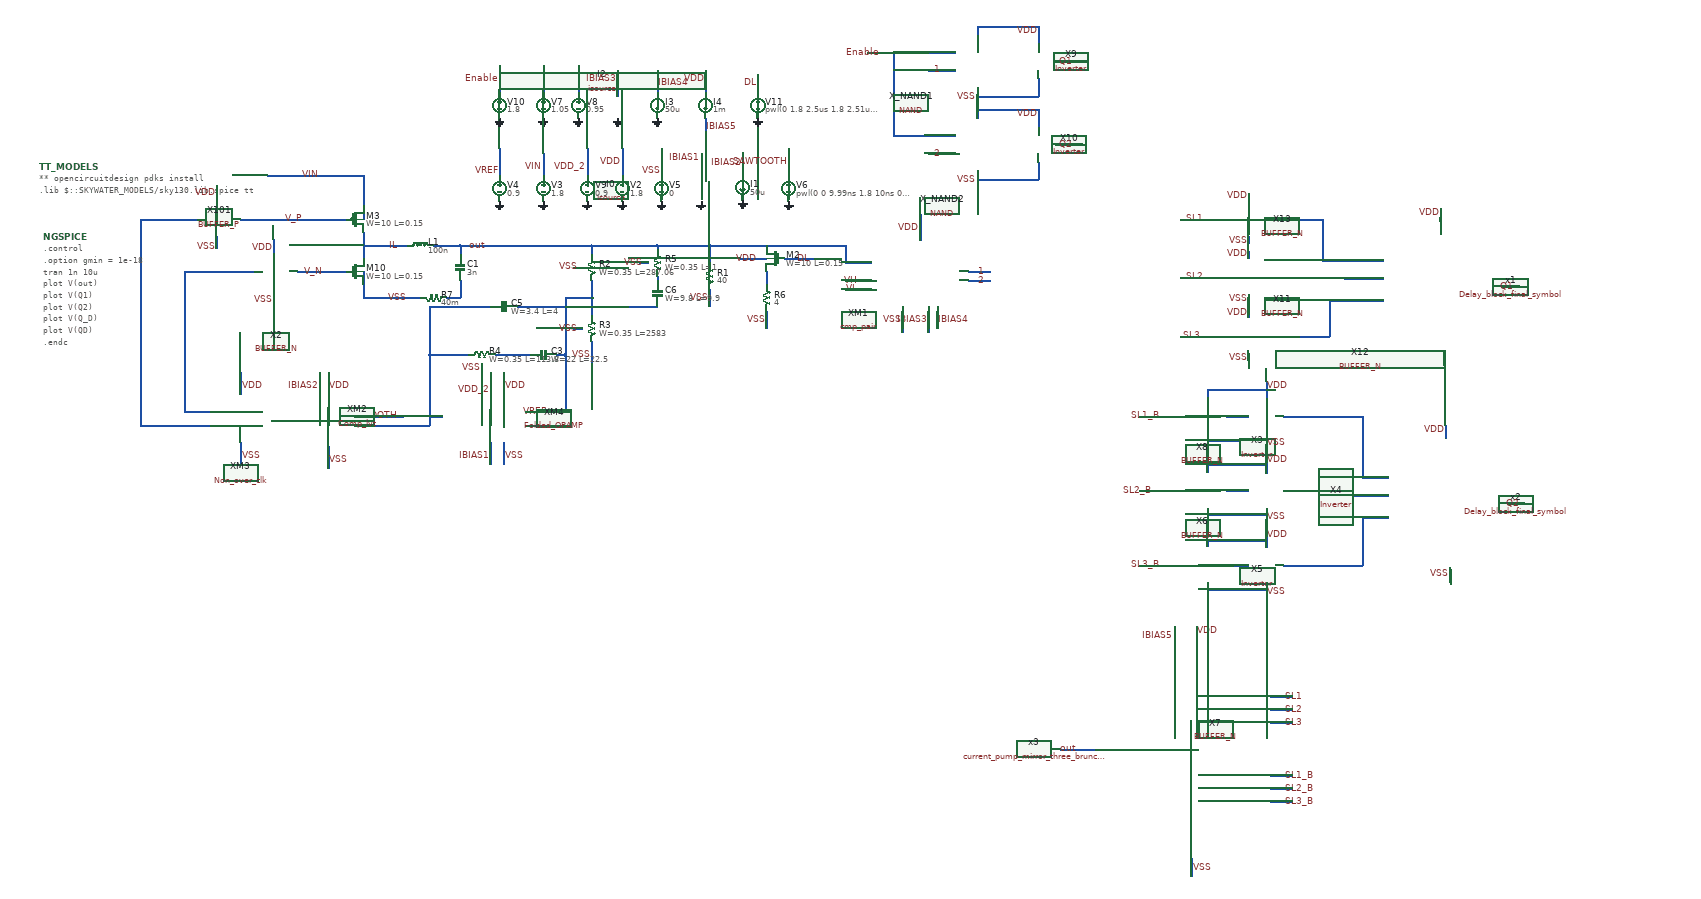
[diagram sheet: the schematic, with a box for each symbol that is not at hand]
v {xschem version=3.0.0 file_version=1.2 }
G {}
K {}
V {}
S {}
E {}
N 3270 1660 3270 1720 {
lab=IL}
N 3270 1600 3270 1630 {
lab=VIN}
N 3180 1630 3230 1630 {
lab=V_P}
N 3270 1530 3270 1600 {
lab=VIN}
N 3050 1530 3270 1530 {
lab=VIN}
N 3270 1780 3270 1810 {
lab=VSS}
N 3270 1690 3330 1690 {
lab=IL}
N 3330 1690 3370 1690 {
lab=IL}
N 3490 1690 3490 1710 {
lab=out}
N 3430 1690 3490 1690 {
lab=out}
N 3490 1770 3490 1810 {
lab=#net1}
N 3490 1690 3600 1690 {
lab=out}
N 3590 1980 3590 2030 {
lab=VDD}
N 3560 1980 3560 2030 {
lab=VDD_2}
N 3590 2140 3590 2190 {
lab=VSS}
N 3560 2140 3560 2190 {
lab=IBIAS1}
N 3640 2100 3690 2100 {
lab=#net2}
N 3640 2070 3690 2070 {
lab=VREF}
N 3680 1480 3680 1530 {
lab=VIN}
N 3780 1470 3780 1530 {
lab=VDD_2}
N 3860 1520 3860 1530 {
lab=VDD}
N 3860 1470 3860 1520 {
lab=VDD}
N 3950 1500 3950 1520 {
lab=VSS}
N 3950 1520 3950 1530 {
lab=VSS}
N 3950 1470 3950 1500 {
lab=VSS}
N 4040 1480 4040 1540 {
lab=IBIAS1}
N 3190 1980 3190 2030 {
lab=VDD}
N 3190 2150 3190 2200 {
lab=VSS}
N 3580 1500 3580 1520 {
lab=VREF}
N 3580 1520 3580 1530 {
lab=VREF}
N 3580 1470 3580 1500 {
lab=VREF}
N 3690 2100 3720 2100 {
lab=#net2}
N 3170 1980 3170 2030 {
lab=IBIAS2}
N 4240 1470 4240 1530 {
lab=SAWTOOTH}
N 2990 1630 3180 1630 {
lab=V_P}
N 3600 1690 3780 1690 {
lab=out}
N 3790 1690 3790 1710 {
lab=out}
N 3790 1770 3790 1820 {
lab=#net2}
N 3790 1910 3790 1960 {
lab=VSS}
N 3570 1940 3650 1940 {
lab=#net3}
N 3420 1940 3510 1940 {
lab=#net4}
N 3420 1940 3420 2080 {
lab=#net4}
N 3730 1940 3730 2070 {
lab=#net2}
N 3710 1940 3730 1940 {
lab=#net2}
N 3420 1830 3560 1830 {
lab=#net4}
N 3620 1830 3730 1830 {
lab=#net2}
N 3730 1870 3730 1940 {
lab=#net2}
N 3420 2080 3450 2080 {
lab=#net4}
N 3730 2070 3730 2100 {
lab=#net2}
N 3720 2100 3730 2100 {
lab=#net2}
N 3790 1690 3940 1690 {
lab=out}
N 3940 1690 3940 1700 {
lab=out}
N 3940 1760 3940 1770 {
lab=#net5}
N 3780 1690 3790 1690 {
lab=out}
N 3730 1810 3730 1870 {
lab=#net2}
N 3730 1810 3790 1810 {
lab=#net2}
N 3790 1820 3790 1850 {
lab=#net2}
N 4060 1690 4060 1730 {
lab=out}
N 3940 1690 4060 1690 {
lab=out}
N 4060 1790 4060 1830 {
lab=VSS}
N 3250 2100 3420 2100 {
lab=#net4}
N 3420 2080 3420 2100 {
lab=#net4}
N 3180 1750 3230 1750 {
lab=V_N}
N 3270 1750 3270 1780 {
lab=VSS}
N 4060 1690 4190 1690 {
lab=out}
N 4190 1840 4190 1880 {
lab=VSS}
N 4190 1750 4190 1780 {
lab=#net6}
N 4230 1720 4300 1720 {
lab=DL}
N 2990 1980 2990 2030 {
lab=VDD}
N 2990 2140 2990 2190 {
lab=VSS}
N 2760 1630 2890 1630 {
lab=#net7}
N 2760 1630 2760 2070 {
lab=#net7}
N 2935 1670 2935 1697.5 {
lab=VSS}
N 2935 1552.5 2935 1587.5 {
lab=VDD}
N 3120 1750 3180 1750 {
lab=V_N}
N 2860 1750 3020 1750 {
lab=#net8}
N 2860 1750 2860 1840 {
lab=#net8}
N 3065 1790 3065 1827.5 {
lab=VSS}
N 3065 1677.5 3065 1707.5 {
lab=VDD}
N 2860 2070 2920 2070 {
lab=#net8}
N 2860 1840 2860 2070 {
lab=#net8}
N 2760 2100 2920 2100 {
lab=#net7}
N 2760 2070 2760 2100 {
lab=#net7}
N 3420 1830 3420 1940 {
lab=#net4}
N 3790 1830 3840 1830 {
lab=#net2}
N 3840 1830 3940 1830 {
lab=#net2}
N 3590 2140 3590 2190 {
lab=VSS}
N 4130 1720 4190 1720 {
lab=VDD}
N 4135 1477.5 4135 1527.5 {
lab=IBIAS2}
N 3070 2090 3120 2090 {
lab=#net9}
N 3250 2080 3360 2080 {
lab=SAWTOOTH}
N 3540 1960 3540 1980 {
lab=VSS}
N 3900 1730 3920 1730 {
lab=VSS}
N 3750 1740 3770 1740 {
lab=VSS}
N 3750 1880 3770 1880 {
lab=VSS}
N 3270 1810 3400 1810 {
lab=VSS}
N 3460 1810 3490 1810 {
lab=#net1}
N 3060 2090 3070 2090 {
lab=#net9}
N 4650 1750 4700 1750 {
lab=1}
N 4650 1770 4700 1770 {
lab=2}
N 4580 1830 4580 1880 {
lab=IBIAS4}
N 4560 1830 4560 1890 {
lab=IBIAS3}
N 4500 1830 4500 1890 {
lab=VSS}
N 4540 1620 4540 1680 {
lab=VDD}
N 4370 1730 4430 1730 {
lab=out}
N 4370 1770 4430 1770 {
lab=VH}
N 4370 1790 4430 1790 {
lab=VL}
N 4370 1690 4370 1730 {
lab=out}
N 3680 1280 3680 1340 {
lab=VH}
N 3760 1280 3760 1340 {
lab=VL}
N 3850 1290 3850 1350 {
lab=IBIAS3}
N 3940 1290 3940 1340 {
lab=IBIAS4}
N 4480 1440 4620 1440 {
lab=Enable}
N 4480 1250 4620 1250 {
lab=Enable}
N 4420 1250 4480 1250 {
lab=Enable}
N 4560 1290 4620 1290 {
lab=1}
N 4560 1480 4620 1480 {
lab=2}
N 4850 1270 4910 1270 {
lab=Q1}
N 4850 1460 4910 1460 {
lab=Q2}
N 4910 1270 4920 1270 {
lab=Q1}
N 3580 1280 3580 1340 {
lab=Enable}
N 4170 1320 4170 1340 {
lab=DL}
N 4170 1300 4170 1320 {
lab=DL}
N 4190 1690 4370 1690 {
lab=out}
N 4670 1520 4670 1540 {
lab=VSS}
N 4670 1540 4810 1540 {
lab=VSS}
N 4810 1500 4810 1540 {
lab=VSS}
N 4670 1380 4670 1400 {
lab=VDD}
N 4670 1380 4810 1380 {
lab=VDD}
N 4810 1380 4810 1420 {
lab=VDD}
N 4670 1330 4670 1350 {
lab=VSS}
N 4670 1350 4810 1350 {
lab=VSS}
N 4810 1310 4810 1350 {
lab=VSS}
N 4670 1190 4670 1210 {
lab=VDD}
N 4670 1190 4810 1190 {
lab=VDD}
N 4810 1190 4810 1230 {
lab=VDD}
N 4480 1250 4480 1440 {
lab=Enable}
N 5727.5 1605 5727.5 1635 {
lab=VDD}
N 5867.5 1785 5907.5 1785 {
lab=Q1}
N 5737.5 1935 5737.5 1965 {
lab=VSS}
N 5547.5 1725 5597.5 1725 {
lab=#net10}
N 5547.5 1765 5597.5 1765 {
lab=#net11}
N 5547.5 1815 5597.5 1815 {
lab=#net12}
N 5740 2100 5740 2130 {
lab=VDD}
N 5880 2280 5920 2280 {
lab=Q2}
N 5750 2430 5750 2460 {
lab=VSS}
N 5240 2080 5290 2080 {
lab=#net13}
N 5240 2250 5290 2250 {
lab=#net14}
N 5240 2420 5290 2420 {
lab=#net15}
N 5330 2120 5330 2160 {
lab=VSS}
N 5330 2000 5330 2040 {
lab=VDD}
N 5330 2290 5330 2330 {
lab=VSS}
N 5330 2170 5330 2210 {
lab=VDD}
N 5330 2460 5330 2500 {
lab=VSS}
N 5330 2340 5330 2380 {
lab=VDD}
N 5550 2220 5610 2220 {
lab=#net16}
N 5550 2080 5550 2220 {
lab=#net16}
N 5370 2080 5550 2080 {
lab=#net16}
N 5370 2250 5470 2250 {
lab=#net17}
N 5470 2250 5470 2260 {
lab=#net17}
N 5470 2260 5610 2260 {
lab=#net17}
N 5550 2310 5610 2310 {
lab=#net18}
N 5550 2310 5550 2420 {
lab=#net18}
N 5370 2420 5550 2420 {
lab=#net18}
N 5170 2560 5170 2600 {
lab=VDD}
N 5340 2900 5390 2900 {
lab=SL1_B}
N 5340 2930 5390 2930 {
lab=SL2_B}
N 5340 2960 5390 2960 {
lab=SL3_B}
N 5160 3090 5160 3130 {
lab=VSS}
N 4050 1290 4050 1340 {
lab=VDD}
N 4050 1400 4050 1430 {
lab=IBIAS5}
N 5120 2560 5120 2600 {
lab=IBIAS5}
N 5340 2720 5390 2720 {
lab=SL1}
N 5340 2750 5390 2750 {
lab=SL2}
N 5340 2780 5390 2780 {
lab=SL3}
N 4860 2840 4940 2840 {
lab=out}
N 5040 2250 5140 2250 {
lab=SL2_B}
N 5040 2420 5140 2420 {
lab=SL3_B}
N 5040 2080 5140 2080 {
lab=SL1_B}
N 5195 2020 5195 2037.5 {
lab=VDD}
N 5195 2020 5330 2020 {
lab=VDD}
N 5195 2120 5195 2135 {
lab=VSS}
N 5195 2135 5330 2135 {
lab=VSS}
N 5195 2190 5195 2207.5 {
lab=VDD}
N 5195 2190 5330 2190 {
lab=VDD}
N 5195 2290 5195 2305 {
lab=VSS}
N 5195 2305 5330 2305 {
lab=VSS}
N 5195 2362.5 5195 2377.5 {
lab=VDD}
N 5195 2362.5 5330 2362.5 {
lab=VDD}
N 5195 2460 5195 2475 {
lab=VSS}
N 5195 2475 5330 2475 {
lab=VSS}
N 5135 1762.5 5235 1762.5 {
lab=SL2}
N 5135 1897.5 5235 1897.5 {
lab=SL3}
N 5135 1630 5235 1630 {
lab=SL1}
N 5290 1840 5290 1855 {
lab=VDD}
N 5290 1937.5 5290 1952.5 {
lab=VSS}
N 5290 1705 5290 1720 {
lab=VDD}
N 5290 1802.5 5290 1817.5 {
lab=VSS}
N 5290 1572.5 5290 1587.5 {
lab=VDD}
N 5290 1670 5290 1685 {
lab=VSS}
N 5457.5 1725 5547.5 1725 {
lab=#net10}
N 5457.5 1630 5457.5 1725 {
lab=#net10}
N 5335 1630 5457.5 1630 {
lab=#net10}
N 5335 1762.5 5507.5 1762.5 {
lab=#net11}
N 5507.5 1765 5547.5 1765 {
lab=#net11}
N 5507.5 1762.5 5507.5 1765 {
lab=#net11}
N 5475 1815 5547.5 1815 {
lab=#net12}
N 5475 1815 5475 1890 {
lab=#net12}
N 5475 1890 5475 1892.5 {
lab=#net12}
N 5475 1892.5 5475 1895 {
lab=#net12}
N 5475 1895 5475 1897.5 {
lab=#net12}
N 5335 1897.5 5475 1897.5 {
lab=#net12}
C {sky130_fd_pr/pfet_01v8.sym} 3250 1630 0 0 {name=M3
L=0.15
W=10
nf=1
mult=450
ad="'int((nf+1)/2) * W/nf * 0.29'" 
pd="'2*int((nf+1)/2) * (W/nf + 0.29)'"
as="'int((nf+2)/2) * W/nf * 0.29'" 
ps="'2*int((nf+2)/2) * (W/nf + 0.29)'"
nrd="'0.29 / W'" nrs="'0.29 / W'"
sa=0 sb=0 sd=0
model=pfet_01v8
spiceprefix=X
}
C {devices/ind.sym} 3400 1690 3 0 {name=L1
m=1
value=100n
footprint=1206
device=inductor}
C {devices/capa.sym} 3490 1740 0 0 {name=C1
m=1
value=3n
footprint=1206
device="ceramic capacitor"}
C {devices/code.sym} 2530 1510 0 0 {name=TT_MODELS
only_toplevel=true
format="tcleval( @value )"
value="
** opencircuitdesign pdks install
.lib $::SKYWATER_MODELS/sky130.lib.spice tt

"
spice_ignore=false}
C {devices/code_shown.sym} 2540 1670 0 0 {name=NGSPICE
only_toplevel=true
value="

.control

.option gmin = 1e-18
tran 1n 10u
plot V(out)
plot V(Q1)
plot V(Q2) 
plot V(Q_D)
plot V(QD)
.endc
" }
C {devices/lab_wire.sym} 3550 1690 0 0 {name=l4 sig_type=std_logic lab=out}
C {devices/lab_wire.sym} 3350 1690 0 0 {name=l6 sig_type=std_logic lab=IL}
C {devices/lab_wire.sym} 3170 1530 0 0 {name=l5 sig_type=std_logic lab=VIN}
C {devices/vsource.sym} 3680 1560 0 0 {name=V3 value=1.8}
C {devices/gnd.sym} 3680 1590 0 0 {name=l7 lab=GND}
C {devices/lab_wire.sym} 3680 1510 0 0 {name=l2 sig_type=std_logic lab=VIN}
C {devices/gnd.sym} 4040 1590 0 0 {name=l19 lab=GND}
C {devices/lab_wire.sym} 4040 1490 0 0 {name=l22 sig_type=std_logic lab=IBIAS1}
C {devices/isource.sym} 4040 1560 0 0 {name=I0 value=50u}
C {devices/vsource.sym} 3780 1560 0 0 {name=V9 value=0.9}
C {devices/gnd.sym} 3780 1590 0 0 {name=l42 lab=GND}
C {devices/lab_wire.sym} 3780 1510 0 0 {name=l8 sig_type=std_logic lab=VDD_2}
C {devices/vsource.sym} 3860 1560 0 0 {name=V2 value=1.8}
C {devices/gnd.sym} 3860 1590 0 0 {name=l18 lab=GND}
C {devices/vsource.sym} 3950 1560 0 0 {name=V5 value=0}
C {devices/gnd.sym} 3950 1590 0 0 {name=l26 lab=GND}
C {devices/lab_wire.sym} 3950 1520 0 0 {name=l10 sig_type=std_logic lab=VSS}
C {devices/lab_wire.sym} 3590 2010 0 1 {name=l13 sig_type=std_logic lab=VDD}
C {devices/lab_wire.sym} 3560 2020 0 0 {name=l14 sig_type=std_logic lab=VDD_2}
C {devices/lab_wire.sym} 3370 1810 0 0 {name=l1 sig_type=std_logic lab=VSS}
C {devices/lab_wire.sym} 3590 2170 0 1 {name=l15 sig_type=std_logic lab=VSS}
C {devices/lab_wire.sym} 3560 2170 0 0 {name=l16 sig_type=std_logic lab=IBIAS1}
C {devices/lab_wire.sym} 3190 2010 0 1 {name=l11 sig_type=std_logic lab=VDD}
C {devices/lab_wire.sym} 3190 2180 0 1 {name=l12 sig_type=std_logic lab=VSS}
C {devices/vsource.sym} 3580 1560 0 0 {name=V4 value=0.9}
C {devices/gnd.sym} 3580 1590 0 0 {name=l17 lab=GND}
C {devices/lab_wire.sym} 3580 1520 0 0 {name=l20 sig_type=std_logic lab=VREF}
C {devices/isource.sym} 4135 1557.5 0 1 {name=I1 value=50u}
C {devices/lab_wire.sym} 3170 2010 0 0 {name=l27 sig_type=std_logic lab=IBIAS2}
C {devices/vsource.sym} 4240 1560 0 0 {name=V6 value="pwl(0 0 9.99ns 1.8 10ns 0) r=0"}
C {devices/gnd.sym} 4240 1590 0 0 {name=l28 lab=GND}
C {devices/gnd.sym} 4240 1590 0 0 {name=l29 lab=GND}
C {devices/lab_wire.sym} 4240 1500 0 0 {name=l30 sig_type=std_logic lab=SAWTOOTH}
C {devices/lab_wire.sym} 3790 1940 0 0 {name=l31 sig_type=std_logic lab=VSS}
C {devices/lab_wire.sym} 3690 2070 0 0 {name=l33 sig_type=std_logic lab=VREF}
C {devices/lab_wire.sym} 3350 2080 0 0 {name=l32 sig_type=std_logic lab=SAWTOOTH}
C {devices/lab_wire.sym} 4060 1810 0 0 {name=l21 sig_type=std_logic lab=VSS}
C {sky130_fd_pr/pfet_01v8.sym} 4210 1720 0 1 {name=M2
L=0.15
W=10
nf=1
mult=450
ad="'int((nf+1)/2) * W/nf * 0.29'" 
pd="'2*int((nf+1)/2) * (W/nf + 0.29)'"
as="'int((nf+2)/2) * W/nf * 0.29'" 
ps="'2*int((nf+2)/2) * (W/nf + 0.29)'"
nrd="'0.29 / W'" nrs="'0.29 / W'"
sa=0 sb=0 sd=0
model=pfet_01v8
spiceprefix=X
}
C {devices/lab_wire.sym} 4190 1860 0 0 {name=l23 sig_type=std_logic lab=VSS}
C {devices/lab_wire.sym} 2990 2010 0 1 {name=l35 sig_type=std_logic lab=VDD}
C {devices/lab_wire.sym} 2990 2170 0 1 {name=l37 sig_type=std_logic lab=VSS}
C {DC_DC_Converter/BUFFER/BUFFER_PMOS/BUFFER_P.sym} 2870 1680 0 0 {name=X101}
C {devices/lab_wire.sym} 2935 1570 0 0 {name=l38 sig_type=std_logic lab=VDD}
C {devices/lab_wire.sym} 2935 1692.5 0 0 {name=l40 sig_type=std_logic lab=VSS}
C {DC_DC_Converter/BUFFER/BUFFER_NMOS/BUFFER_N.sym} 2930 1830 0 0 {name=X2}
C {devices/lab_wire.sym} 3065 1815 0 0 {name=l39 sig_type=std_logic lab=VSS}
C {devices/lab_wire.sym} 3065 1695 0 0 {name=l41 sig_type=std_logic lab=VDD}
C {DC_DC_Converter/Non_Overlap_Clk/Non_over_clk.sym} 3190 2350 0 1 {name=XM3}
C {devices/lab_wire.sym} 3130 1630 0 0 {name=l3 sig_type=std_logic lab=V_P}
C {devices/lab_wire.sym} 3180 1750 0 0 {name=l43 sig_type=std_logic lab=V_N}
C {DC_DC_Converter/Folded_OPAMP/Folded_OPAMP.sym} 3790 2250 0 1 {name=XM4}
C {devices/lab_wire.sym} 4290 1720 0 0 {name=l96 sig_type=std_logic lab=DL}
C {sky130_fd_pr/cap_mim_m3_1.sym} 3590 1830 3 0 {name=C5 model=cap_mim_m3_1 W=3.4 L=4 MF=1 spiceprefix=X}
C {sky130_fd_pr/cap_mim_m3_1.sym} 3680 1940 3 0 {name=C3 model=cap_mim_m3_1 W=22 L=22.5 MF=1 spiceprefix=X}
C {sky130_fd_pr/cap_mim_m3_1.sym} 3940 1800 0 0 {name=C6 model=cap_mim_m3_1 W=9.8 L=9.9 MF=1 spiceprefix=X}
C {devices/lab_wire.sym} 3860 1500 0 0 {name=l97 sig_type=std_logic lab=VDD}
C {devices/lab_wire.sym} 4170 1720 0 0 {name=l98 sig_type=std_logic lab=VDD}
C {sky130_fd_pr/nfet_01v8.sym} 3250 1750 0 0 {name=M10
L=0.15
W=10
nf=1 
mult=150
ad="'int((nf+1)/2) * W/nf * 0.29'" 
pd="'2*int((nf+1)/2) * (W/nf + 0.29)'"
as="'int((nf+2)/2) * W/nf * 0.29'" 
ps="'2*int((nf+2)/2) * (W/nf + 0.29)'"
nrd="'0.29 / W'" nrs="'0.29 / W'"
sa=0 sb=0 sd=0
model=nfet_01v8
spiceprefix=X
}
C {devices/lab_wire.sym} 4135 1502.5 0 0 {name=l24 sig_type=std_logic lab=IBIAS2}
C {sky130_fd_pr/res_high_po_0p35.sym} 3540 1940 3 0 {name=R4
W=0.35
L=113.8
model=res_high_po_0p35
spiceprefix=X
mult=1}
C {devices/lab_wire.sym} 3540 1970 3 0 {name=l9 sig_type=std_logic lab=VSS}
C {sky130_fd_pr/res_high_po_0p35.sym} 3940 1730 0 0 {name=R5
W=0.35
L=1
model=res_high_po_0p35
spiceprefix=X
mult=1}
C {devices/lab_wire.sym} 3910 1730 0 0 {name=l44 sig_type=std_logic lab=VSS}
C {sky130_fd_pr/res_high_po_0p35.sym} 3790 1740 0 0 {name=R2
W=0.35
L=287.06
model=res_high_po_0p35
spiceprefix=X
mult=1}
C {devices/lab_wire.sym} 3760 1740 0 0 {name=l45 sig_type=std_logic lab=VSS}
C {sky130_fd_pr/res_high_po_0p35.sym} 3790 1880 0 0 {name=R3
W=0.35
L=2583
model=res_high_po_0p35
spiceprefix=X
mult=1}
C {devices/lab_wire.sym} 3760 1880 0 0 {name=l46 sig_type=std_logic lab=VSS}
C {devices/res.sym} 3430 1810 1 0 {name=R7
value=40m
footprint=1206
device=resistor
m=1}
C {devices/res.sym} 4060 1760 0 0 {name=R1
value=40
footprint=1206
device=resistor
m=1}
C {devices/res.sym} 4190 1810 0 0 {name=R6
value=4
footprint=1206
device=resistor
m=1}
C {DC_DC_Converter/Comparator/Comp_lvt.sym} 3270 2160 0 1 {name=XM2}
C {devices/lab_wire.sym} 4580 1860 0 1 {name=l48 sig_type=std_logic lab=IBIAS4}
C {devices/lab_wire.sym} 4560 1860 0 0 {name=l49 sig_type=std_logic lab=IBIAS3}
C {devices/lab_pin.sym} 4500 1860 0 0 {name=l50 sig_type=std_logic lab=VSS}
C {devices/lab_pin.sym} 4540 1650 0 0 {name=l51 sig_type=std_logic lab=VDD}
C {devices/lab_pin.sym} 4400 1770 1 0 {name=l53 sig_type=std_logic lab=VH}
C {devices/lab_pin.sym} 4400 1790 3 0 {name=l54 sig_type=std_logic lab=VL}
C {DC_DC_Converter/Comparator_Pair/cmp_pair.sym} 4410 1830 0 0 {name=XM1}
C {devices/lab_wire.sym} 4690 1750 0 0 {name=l47 sig_type=std_logic lab=1}
C {devices/lab_wire.sym} 4690 1770 0 0 {name=l87 sig_type=std_logic lab=2}
C {devices/vsource.sym} 3680 1370 0 0 {name=V7 value=1.05}
C {devices/gnd.sym} 3680 1400 0 0 {name=l52 lab=GND}
C {devices/lab_pin.sym} 3680 1310 0 0 {name=l55 sig_type=std_logic lab=VH}
C {devices/vsource.sym} 3760 1370 0 0 {name=V8 value=0.95}
C {devices/gnd.sym} 3760 1400 0 0 {name=l56 lab=GND}
C {devices/lab_pin.sym} 3760 1310 0 0 {name=l57 sig_type=std_logic lab=VL}
C {devices/gnd.sym} 3850 1400 0 0 {name=l58 lab=GND}
C {devices/isource.sym} 3850 1370 0 0 {name=I2 value=50u}
C {devices/isource.sym} 3940 1370 0 0 {name=I3 value=50u}
C {devices/gnd.sym} 3940 1400 0 0 {name=l60 lab=GND}
C {devices/lab_wire.sym} 3850 1310 0 0 {name=l59 sig_type=std_logic lab=IBIAS3}
C {devices/lab_wire.sym} 3940 1320 0 1 {name=l61 sig_type=std_logic lab=IBIAS4}
C {devices/noconn.sym} 4700 1770 0 1 {name=l62}
C {devices/noconn.sym} 4700 1750 0 1 {name=l63}
C {DC_DC_Converter/NAND_GATE/NAND.sym} 4600 1340 0 0 {name=X_NAND1}
C {DC_DC_Converter/NAND_GATE/NAND.sym} 4600 1530 0 0 {name=X_NAND2}
C {devices/lab_pin.sym} 4670 1540 0 0 {name=l84 sig_type=std_logic lab=VSS}
C {DC_DC_Converter/Inverter/Inverter.sym} 4740 1290 0 0 {name=X9}
C {DC_DC_Converter/Inverter/Inverter.sym} 4740 1480 0 0 {name=X10}
C {devices/lab_wire.sym} 4890 1460 0 0 {name=l86 sig_type=std_logic lab=Q2}
C {devices/lab_wire.sym} 4590 1290 0 0 {name=l64 sig_type=std_logic lab=1}
C {devices/lab_wire.sym} 4590 1480 0 0 {name=l88 sig_type=std_logic lab=2}
C {devices/lab_wire.sym} 4450 1250 0 0 {name=l91 sig_type=std_logic lab=Enable}
C {devices/lab_pin.sym} 4810 1390 0 0 {name=l94 sig_type=std_logic lab=VDD}
C {devices/lab_wire.sym} 4890 1270 0 0 {name=l79 sig_type=std_logic lab=Q1}
C {devices/gnd.sym} 3580 1400 0 0 {name=l89 lab=GND}
C {devices/lab_pin.sym} 3580 1310 0 0 {name=l90 sig_type=std_logic lab=Enable}
C {devices/vsource.sym} 3580 1370 0 0 {name=V10 value=1.8}
C {devices/gnd.sym} 4135 1587.5 0 0 {name=l25 lab=GND}
C {devices/vsource.sym} 4170 1370 0 0 {name=V11 value="pwl(0 1.8 2.5us 1.8 2.51us 0 5us 0) r=0"}
C {devices/gnd.sym} 4170 1400 0 0 {name=l65 lab=GND}
C {devices/gnd.sym} 4170 1400 0 0 {name=l66 lab=GND}
C {devices/lab_wire.sym} 4170 1320 0 0 {name=l67 sig_type=std_logic lab=DL}
C {devices/lab_pin.sym} 4670 1350 0 0 {name=l34 sig_type=std_logic lab=VSS}
C {devices/lab_pin.sym} 4810 1200 0 0 {name=l36 sig_type=std_logic lab=VDD}
C {DC_DC_Converter/Delay_block_revised/Delay_block_final_symbol.sym} 6157.5 1905 0 1 {name=x1}
C {devices/lab_pin.sym} 5727.5 1615 0 0 {name=l68 sig_type=std_logic lab=VDD}
C {devices/lab_pin.sym} 5737.5 1945 0 0 {name=l69 sig_type=std_logic lab=VSS}
C {devices/lab_wire.sym} 5897.5 1785 0 0 {name=l70 sig_type=std_logic lab=Q1}
C {devices/lab_wire.sym} 5190 1630 0 0 {name=l71 sig_type=std_logic lab=SL1}
C {devices/lab_wire.sym} 5190 1762.5 0 0 {name=l72 sig_type=std_logic lab=SL2}
C {devices/lab_wire.sym} 5182.5 1897.5 0 0 {name=l73 sig_type=std_logic lab=SL3}
C {DC_DC_Converter/Delay_block_revised/Delay_block_final_symbol.sym} 6170 2400 0 1 {name=x2}
C {devices/lab_pin.sym} 5740 2110 0 0 {name=l74 sig_type=std_logic lab=VDD}
C {devices/lab_pin.sym} 5750 2440 0 0 {name=l75 sig_type=std_logic lab=VSS}
C {devices/lab_wire.sym} 5910 2280 0 0 {name=l76 sig_type=std_logic lab=Q2}
C {devices/lab_wire.sym} 5090 2080 0 0 {name=l77 sig_type=std_logic lab=SL1_B}
C {devices/lab_wire.sym} 5070 2250 0 0 {name=l78 sig_type=std_logic lab=SL2_B}
C {devices/lab_wire.sym} 5090 2420 0 0 {name=l80 sig_type=std_logic lab=SL3_B}
C {DC_DC_Converter/Inverter/Inverter.sym} 5400 2100 0 1 {name=X3}
C {devices/lab_pin.sym} 5330 2010 0 1 {name=l81 sig_type=std_logic lab=VDD}
C {DC_DC_Converter/Inverter/Inverter.sym} 5400 2270 0 1 {name=X4}
C {devices/lab_pin.sym} 5330 2180 0 1 {name=l83 sig_type=std_logic lab=VDD}
C {DC_DC_Converter/Inverter/Inverter.sym} 5400 2440 0 1 {name=X5}
C {devices/lab_pin.sym} 5330 2350 0 1 {name=l92 sig_type=std_logic lab=VDD}
C {devices/lab_pin.sym} 5330 2480 0 1 {name=l93 sig_type=std_logic lab=VSS}
C {DC_DC_Converter/Current_pump_mirror/current_pump_mirror_three_brunch_symbol.sym} 4440 3040 0 1 {name=x3}
C {devices/lab_pin.sym} 5330 2310 0 1 {name=l82 sig_type=std_logic lab=VSS}
C {devices/lab_pin.sym} 5330 2140 0 1 {name=l85 sig_type=std_logic lab=VSS}
C {devices/lab_pin.sym} 5170 2570 0 1 {name=l95 sig_type=std_logic lab=VDD}
C {devices/lab_wire.sym} 5370 2900 0 1 {name=l99 sig_type=std_logic lab=SL1_B}
C {devices/lab_wire.sym} 5370 2930 0 1 {name=l100 sig_type=std_logic lab=SL2_B}
C {devices/lab_wire.sym} 5370 2960 0 1 {name=l101 sig_type=std_logic lab=SL3_B}
C {devices/lab_pin.sym} 5160 3110 0 1 {name=l102 sig_type=std_logic lab=VSS}
C {devices/isource.sym} 4050 1370 0 0 {name=I4 value=1m}
C {devices/lab_wire.sym} 4050 1420 0 1 {name=l104 sig_type=std_logic lab=IBIAS5}
C {devices/lab_pin.sym} 4050 1310 0 0 {name=l103 sig_type=std_logic lab=VDD}
C {devices/lab_wire.sym} 5120 2580 0 0 {name=l105 sig_type=std_logic lab=IBIAS5}
C {devices/lab_wire.sym} 5370 2720 0 1 {name=l106 sig_type=std_logic lab=SL1}
C {devices/lab_wire.sym} 5370 2750 0 1 {name=l107 sig_type=std_logic lab=SL2}
C {devices/lab_wire.sym} 5370 2780 0 1 {name=l108 sig_type=std_logic lab=SL3}
C {devices/lab_wire.sym} 4900 2840 0 0 {name=l109 sig_type=std_logic lab=out}
C {DC_DC_Converter/BUFFER/BUFFER_NMOS/BUFFER_N.sym} 5330 2330 0 1 {name=X6}
C {DC_DC_Converter/BUFFER/BUFFER_NMOS/BUFFER_N.sym} 5330 2500 0 1 {name=X7}
C {DC_DC_Converter/BUFFER/BUFFER_NMOS/BUFFER_N.sym} 5330 2160 0 1 {name=X8}
C {DC_DC_Converter/BUFFER/BUFFER_NMOS/BUFFER_N.sym} 5425 1842.5 0 1 {name=X11}
C {DC_DC_Converter/BUFFER/BUFFER_NMOS/BUFFER_N.sym} 5425 1977.5 0 1 {name=X12}
C {DC_DC_Converter/BUFFER/BUFFER_NMOS/BUFFER_N.sym} 5425 1710 0 1 {name=X13}
C {devices/lab_pin.sym} 5290 1947.5 0 0 {name=l110 sig_type=std_logic lab=VSS}
C {devices/lab_pin.sym} 5290 1845 0 0 {name=l111 sig_type=std_logic lab=VDD}
C {devices/lab_pin.sym} 5290 1812.5 0 0 {name=l112 sig_type=std_logic lab=VSS}
C {devices/lab_pin.sym} 5290 1710 0 0 {name=l113 sig_type=std_logic lab=VDD}
C {devices/lab_pin.sym} 5290 1680 0 0 {name=l114 sig_type=std_logic lab=VSS}
C {devices/lab_pin.sym} 5290 1577.5 0 0 {name=l115 sig_type=std_logic lab=VDD}
